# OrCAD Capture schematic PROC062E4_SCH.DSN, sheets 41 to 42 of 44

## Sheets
41 41. SoC POWER SUPPLY: size C; title: SoC POWER SUPPLY
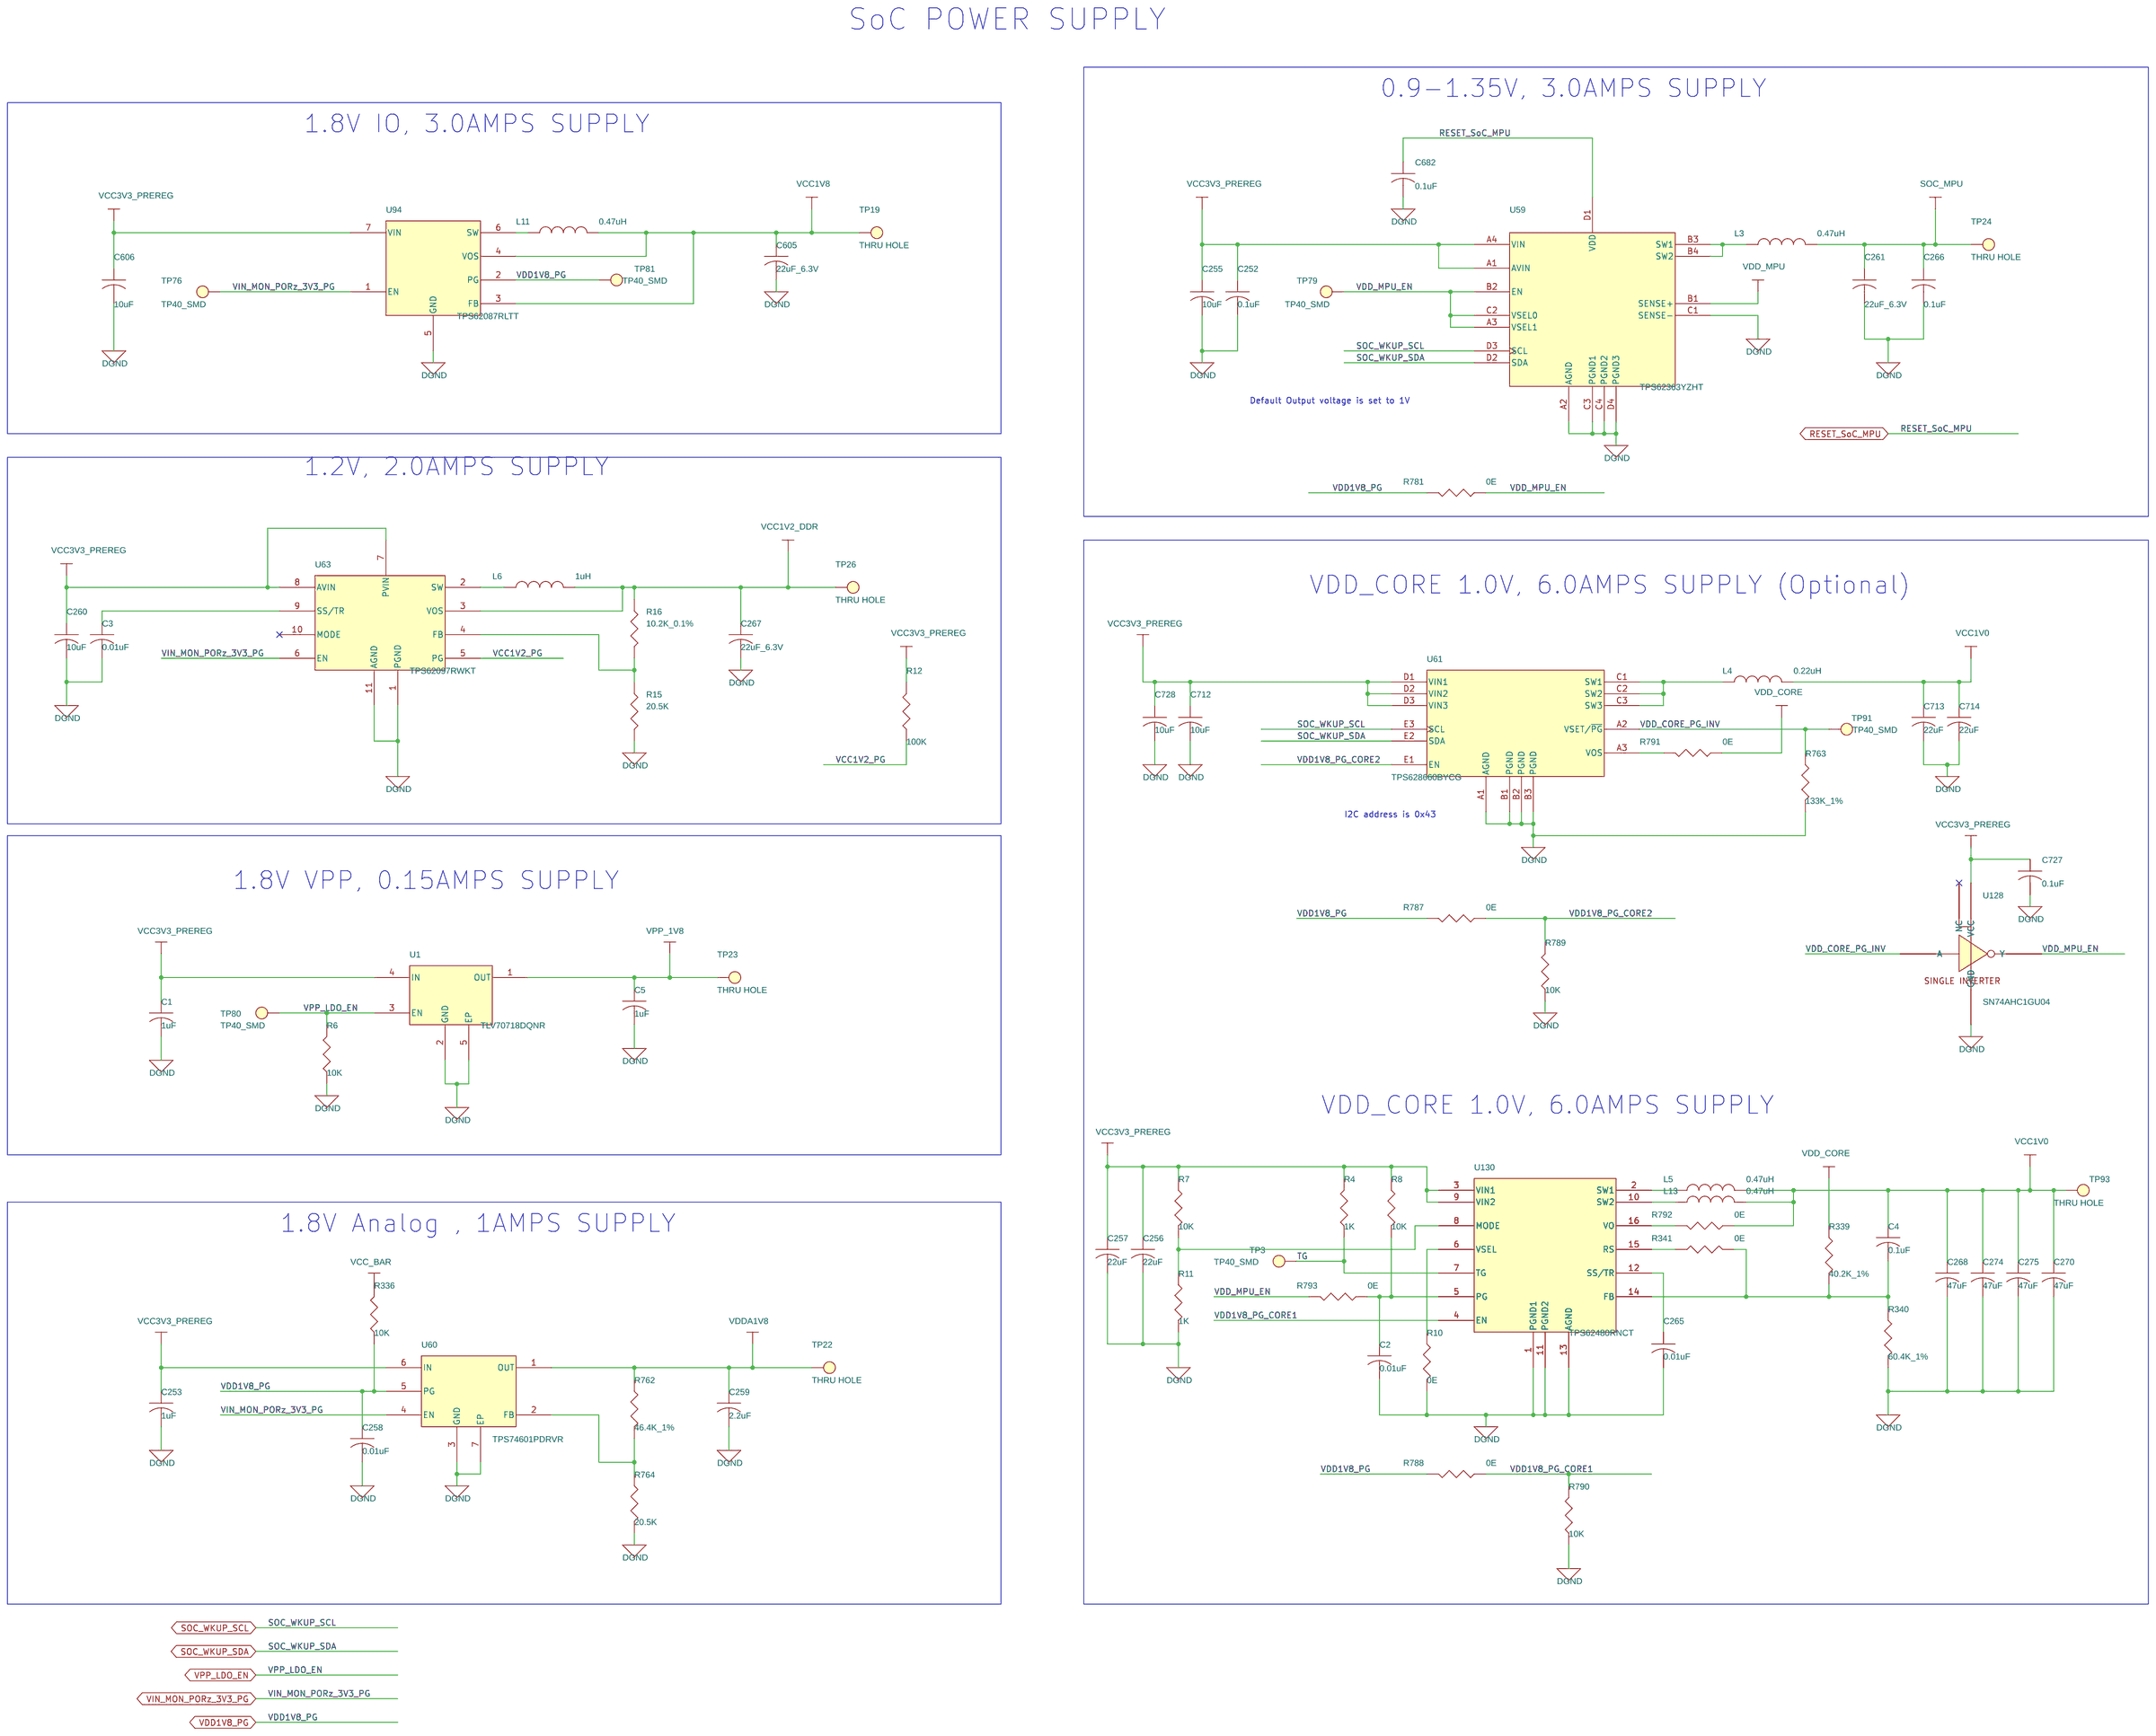
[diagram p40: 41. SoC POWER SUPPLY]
42 42. PERIPHERAL POWER SUPPLY: size C; title: PERIPHERAL POWER SUPPLY

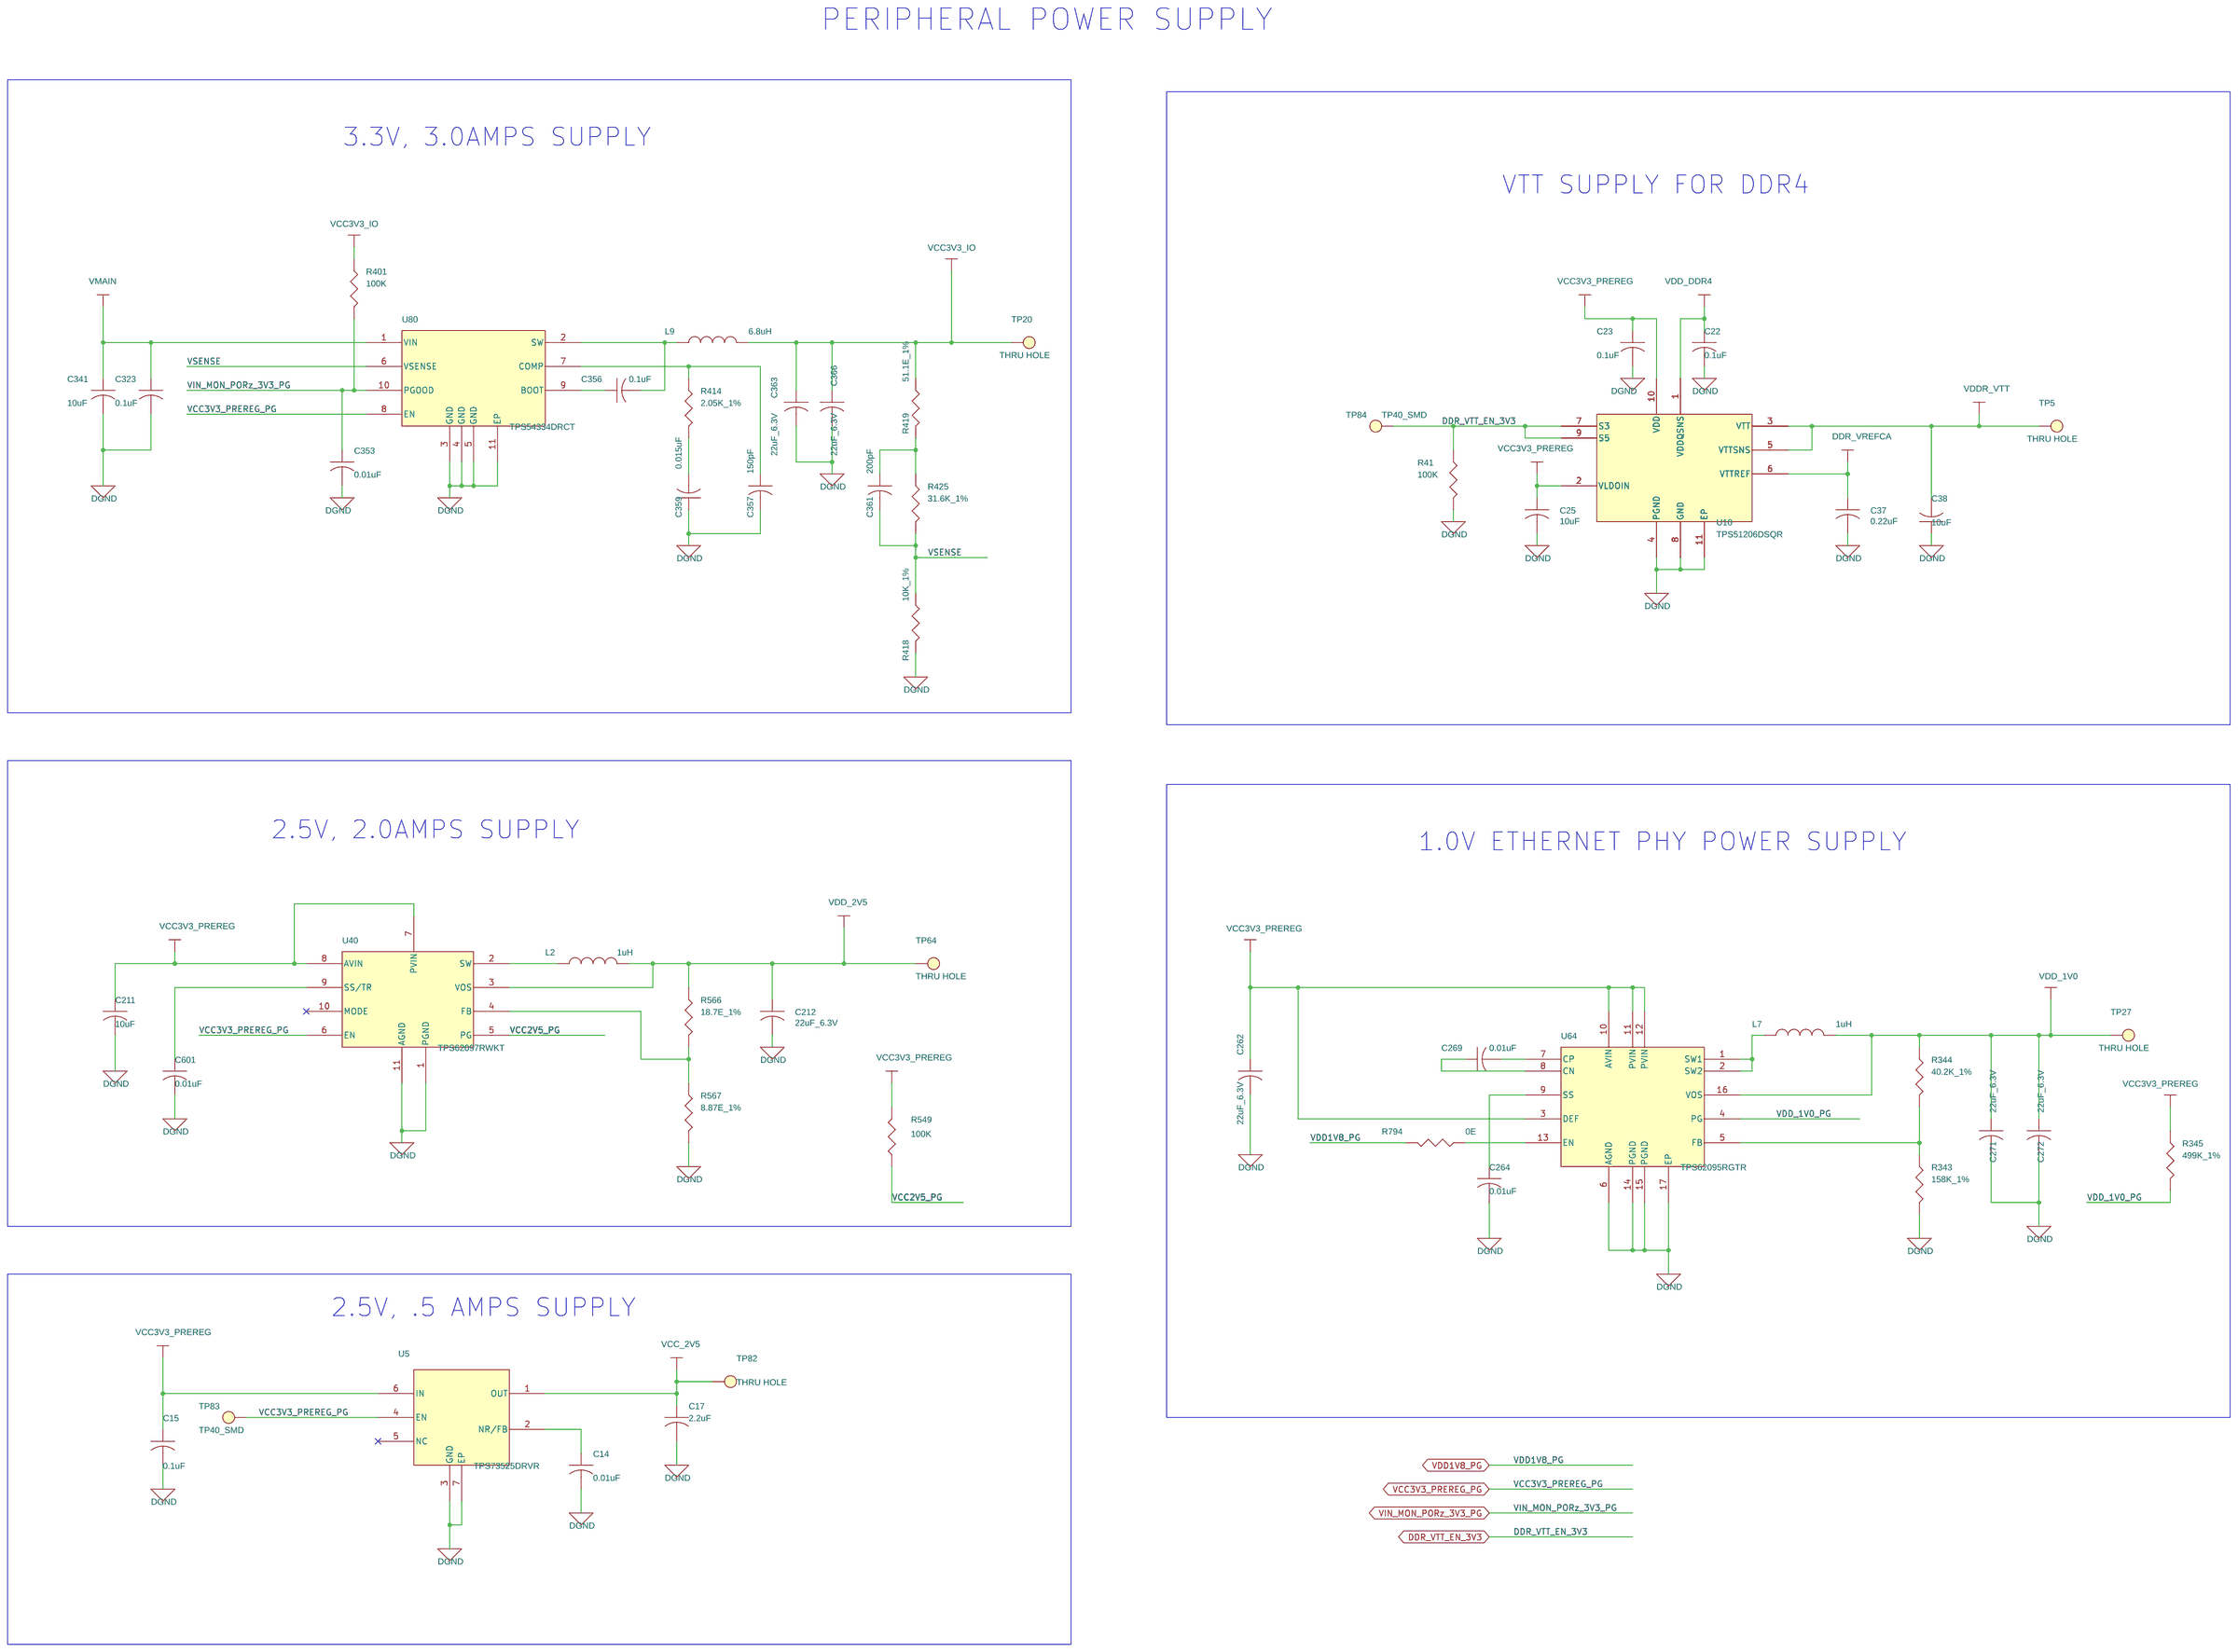
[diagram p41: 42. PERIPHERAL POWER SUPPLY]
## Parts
sheet 41. SoC POWER SUPPLY
C1  1uF  [CAP0603_1]
C2  0.01uF  [CAP0201_0-5]
C3  0.01uF  [CAP0201_0-5]
C4  0.1uF  [CAP0201_0-5]
C5  1uF  [CAP0603_1]
C252  0.1uF  [CAP0201_0-5]
C253  1uF  [CAP0603_1]
C255  10uF  [CAP1206_2]
C256  22uF  [CAP1206_2]
C257  22uF  [CAP1206_2]
C258  0.01uF  [CAP0201_0-5]
C259  2.2uF  [CAP0402_0-75]
C260  10uF  [CAP0603_1]
C261  22uF_6.3V  [CAP0603]
C265  0.01uF  [CAP0402_0-75]
C266  0.1uF  [CAP0201_0-5]
C267  22uF_6.3V  [CAP0603]
C268  47uF  [CAP0603_1]
C270  47uF  [CAP0603_1]
C274  47uF  [CAP0603_1]
C275  47uF  [CAP0603_1]
C605  22uF_6.3V  [CAP0603]
C606  10uF  [CAP1206_2]
C682  0.1uF  [CAP0201_0-5]
C712  10uF  [CAP0603_1]
C713  22uF  [CAP1206_2]
C714  22uF  [CAP1206_2]
C727  0.1uF  [CAP0201_0-5]
C728  10uF  [CAP0603_1]
L3  0.47uH  [IND_XEL4030_170X170_SMD_1-6]
L4  0.22uH  [IND_XAL4020_170X170_SMD_2-1]
L5  0.47uH  [IND_XEL4030_170X170_SMD_1-6]
L6  1uH  [IND_IHLP2020AB_210X210_SMD_1-2]
L11  0.47uH  [IND_XEL4030_170X170_SMD_1-6]
L13  0.47uH  [IND_XEL4030_170X170_SMD_1-6]
R4  1K  [RES0201]
R6  10K  [RES0402_0-5]
R7  10K  [RES0402_0-5]
R8  10K  [RES0402_0-5]
R10  0E  [RES0402_0-5]
R11  1K  [RES0201]
R12  100K  [RES0402_0-5]
R15  20.5K  [RES0402]
R16  10.2K_0.1%  [RES0402]
R336  10K  [RES0402_0-5]
R339  40.2K_1%  [RES0402_0-5]
R340  60.4K_1%  [RES0402_0-5]
R341  0E  [RES0402_0-5]
R762  46.4K_1%  [RES0402]
R763  133K_1%  [RES0402_0-5]
R764  20.5K  [RES0402]
R781  0E  [RES0402_0-5]
R787  0E  [RES0402_0-5]
R788  0E  [RES0402_0-5]
R789  10K  [RES0402_0-5]
R790  10K  [RES0402_0-5]
R791  0E  [RES0402_0-5]
R792  0E  [RES0402_0-5]
R793  0E  [RES0402_0-5]
TP3  TP40_SMD  [TP40_SMD]
TP19  THRU HOLE  [TP_40X65]
TP22  THRU HOLE  [TP_40X65]
TP23  THRU HOLE  [TP_40X65]
TP24  THRU HOLE  [TP_40X65]
TP26  THRU HOLE  [TP_40X65]
TP76  TP40_SMD  [TP40_SMD]
TP79  TP40_SMD  [TP40_SMD]
TP80  TP40_SMD  [TP40_SMD]
TP81  TP40_SMD  [TP40_SMD]
TP91  TP40_SMD  [TP40_SMD]
TP93  THRU HOLE  [TP_40X65]
U1  TLV70718DQNR  [X2SON4_TLV71318P_40X40_0-4]
U59  TPS62363YZHT  [DSBGA16_19-68_80X80_0-7]
U60  TPS74601PDRVR  [SON6_25-59_85X85_0-8]
U61  TPS628660BYCG  [WCSP15_13-77_40X70_0-5]
U63  TPS62097RWKT  [VQFNHR11_TPS62097_80X80_1]
U94  TPS62087RLTT  [VSONHR7_TPS62085_80X80_1]
U128  SN74AHC1GU04  [SOT23-5]
U130  TPS62480RNCT  [VQFNHR16_TPS62480_100X120_1]
sheet 42. PERIPHERAL POWER SUPPLY
C14  0.01uF  [CAP0201_0-5]
C15  0.1uF  [CAP0201_0-5]
C17  2.2uF  [CAP0402_0-75]
C22  0.1uF  [CAP0201_0-5]
C23  0.1uF  [CAP0201_0-5]
C25  10uF  [CAP0603_1]
C37  0.22uF  [CAP0402_0-75]
C38  10uF  [CAP0603_1]
C211  10uF  [CAP0603_1]
C212  22uF_6.3V  [CAP0603]
C262  22uF_6.3V  [CAP0603]
C264  0.01uF  [CAP0201_0-5]
C269  0.01uF  [CAP0201_0-5]
C271  22uF_6.3V  [CAP0603]
C272  22uF_6.3V  [CAP0603]
C323  0.1uF  [CAP0603_1]
C341  10uF  [CAP1206_2]
C353  0.01uF  [CAP0201_0-5]
C356  0.1uF  [CAP0201_0-5]
C357  150pF  [CAP0402_0-75]
C359  0.015uF  [CAP0402]
C361  200pF  [CAP0402_0-75]
C363  22uF_6.3V  [CAP0603]
C366  22uF_6.3V  [CAP0603]
C601  0.01uF  [CAP0201_0-5]
L2  1uH  [IND_IHLP2020AB_210X210_SMD_1-2]
L7  1uH  [IND_XFL4020_170X170_SMD_2-1]
L9  6.8uH  [IND_74439346068_260X270_SMD_6-1]
R41  100K  [RES0402_0-5]
R343  158K_1%  [RES0402_0-5]
R344  40.2K_1%  [RES0402_0-5]
R345  499K_1%  [RES0402]
R401  100K  [RES0402_0-5]
R414  2.05K_1%  [RES0402]
R418  10K_1%  [RES0402_0-5]
R419  51.1E_1%  [RES0402_0-5]
R425  31.6K_1%  [RES0402]
R549  100K  [RES0402_0-5]
R566  18.7E_1%  [RES0402]
R567  8.87E_1%  [RES0402]
R794  0E  [RES0402_0-5]
TP5  THRU HOLE  [TP_40X65]
TP20  THRU HOLE  [TP_40X65]
TP27  THRU HOLE  [TP_40X65]
TP64  THRU HOLE  [TP_40X65]
TP82  THRU HOLE  [TP_40X65]
TP83  TP40_SMD  [TP40_SMD]
TP84  TP40_SMD  [TP40_SMD]
U5  TPS73525DRVR  [SON6_25-59_85X85_0-8]
U10  TPS51206DSQR  [DFN10_15-74_80X80_0-8]
U40  TPS62097RWKT  [VQFNHR11_TPS62097_80X80_1]
U64  TPS62095RGTR  [QFN16_19-68_120X120_1]
U80  TPS54334DRCT  [SON10_19-68_125X125_1]

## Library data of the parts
C1 C5 C253 = CAP: CAP CERAMIC 1uF 25V 10% X5R 0603; Chkd/date: MANIRAJA/230118; Crtd /date: MANIRAJA/230118; Custom_Duty: 15%; Customs_HS_Code: 85322990; Distributor_name: DIGIKEY; Distributor_part_number: 478-5142-1-ND; Height: 0.94MM; Mfr_name: AVX CORPORATION; Mfr_part_number: 06033D105KAT2A; Mistral Part No: 120010080040-R; Package: 0603; Part_type: CAPACITORS\CERAMIC; Project: TI_MAXIE_CPB; RoHS: RoHS; Temperature: -55°C+85°C; Tolerance: 10%; Voltage: 25V; Wattage: NA; Weight: 2mg; Datasheet: Y:\MIS_DATABASE\DATASHEETS\CAPACITORS\AVX_MLC.PDF
C2 C3 C14 C258 C264 C269 C353 C601 = CAP: CAP CERAMIC 0.01uF 25V 10% X5R 0201; Chkd/date: MANIRAJA/230118; Crtd /date: MANIRAJA/230118; Custom_Duty: 15%; Customs_HS_Code: 85322990; Distributor_name: DIGIKEY; Distributor_part_number: GRM033R61E103KA12J-ND; Height: 0.33MM; Mfr_name: MURATA; Mfr_part_number: GRM033R61E103KA12J; Mistral Part No: 120018010007-R; Package: 0201; Part_type: CAPACITORS\CERAMIC; Project: TI_MAXIE_CPB; RoHS: RoHS; Temperature: -55°C+85°C; Tolerance: 10%; Voltage: 25V; Wattage: NA; Weight: 0.33mg; Datasheet: Y:\MIS_DATABASE\DATASHEETS\CAPACITORS\GRM033R61E103KA12.PDF
C4 C15 C22 C23 C252 C266 C356 C682 C727 = CAP: CAP CERAMIC 0.1uF 16V 10% X5R 0201; Chkd/date: MANIRAJA/120218; Crtd /date: MANIRAJA/120218; Custom_Duty: 15%; Customs_HS_Code: 85322990; Distributor_name: DIGIKEY; Distributor_part_number: 490-16742-1-ND; Height: 0.33MM; Mfr_name: MURATA; Mfr_part_number: GRM033R61C104KE84J; Mistral Part No: 120009030072-R; Package: 0201; Part_type: CAPACITORS\CERAMIC; Project: TI_MAXIE_CPB; RoHS: RoHS; Temperature: -55°C+85°C; Tolerance: 10%; Voltage: 16V; Wattage: NA; Weight: 0.33mg; Datasheet: Y:\MIS_DATABASE\DATASHEETS\CAPACITORS\GRM033R61C104KE84.PDF
C255 C341 = CAP: CAP CERAMIC 10uF 50V 10% X5R 1206; Chkd/date: VASANTHA/190814; Crtd /date: BAVISH/230611; Custom_Duty: 15%; Customs_HS_Code: 85322990; Distributor_name: DIGIKEY; Distributor_part_number: 445-5998-1-ND; Footprint Path: Y:\MIS_DATABASE\Library\ALTIUM_TOOL\PCB_FOOTPRINTS\Altium_Footprint_Lib.PcbLib; Height: 1.90MM; Library Path: Y:\MIS_DATABASE\Library\ALTIUM_TOOL\SCHEMATICS_PARTS\MS_DISCRETE_Library.schlib; Mfr_name: TDK CORPORATION; Mfr_part_number: C3216X5R1H106K160AB; Mistral Part No: 120016030005-R; Package: 1206; Part_type: CAPACITORS\CERAMIC; Project: ITS-SINGAL_COND_CARD; RoHS: RoHS; Temperature: -55°C+85°C; Tolerance: 10%; Voltage: 50V; Wattage: NA; Weight: 16.2mg; Datasheet: Y:\MIS_DATABASE\DATASHEETS\CAPACITORS\TDK_C-SER-JUL17.PDF
C256 C257 C713 C714 = CAP: CAP CERAMIC 22uF 16V 20% X7R 1206; Chkd/date: VASANTHA/170117; Crtd /date: VASANTHA/170117; Custom_Duty: 15%; Customs_HS_Code: 85322990; Distributor_name: DIGIKEY; Distributor_part_number: 587-4319-1-ND; Height: 1.90MM; Mfr_name: TAIYO YUDEN; Mfr_part_number: EMK316BB7226ML-T; Mistral Part No: 120017010003-R; Package: 1206; Part_type: CAPACITORS\CERAMIC; Project: TRMM_SMART-M_PS; RoHS: RoHS; Temperature: -55°C+125°C; Tolerance: 20%; Voltage: 16V; Wattage: NA; Weight: 16.2mg; Datasheet: Y:\MIS_DATABASE\DATASHEETS\CAPACITORS\EMK316BB7226ML.PDF
C17 C259 = CAP: CAP CERAMIC 2.2uF 10V 20% X5R 0402; Chkd/date: MANIRAJA/240118; Crtd /date: MANIRAJA/240118; Custom_Duty: 15%; Customs_HS_Code: 85322990; Distributor_name: DIGIKEY; Distributor_part_number: 490-12254-1-ND; Height: 0.55MM; Mfr_name: MURATA; Mfr_part_number: GRT155R61A225ME01D; Mistral Part No: 120018010016-R; Package: 0402; Part_type: CAPACITORS\CERAMIC; Project: TI_MAXIE_CPB; RoHS: RoHS; Temperature: -55°C+85°C; Tolerance: 20%; Voltage: 10V; Wattage: NA; Weight: 0.65mg; Datasheet: Y:\MIS_DATABASE\DATASHEETS\CAPACITORS\GRT155R61A225ME01.PDF
C25 C38 C211 C260 C712 C728 = CAP: CAP CERAMIC 10uF 10V 10% X5R 0603; Chkd/date: MANIRAJA/230118; Crtd /date: MANIRAJA/230118; Custom_Duty: 15%; Customs_HS_Code: 85322990; Distributor_name: DIGIKEY; Distributor_part_number: 478-10766-1-ND; Height: 0.94MM; Mfr_name: AVX CORPORATION; Mfr_part_number: 0603ZD106KAT2A; Mistral Part No: 120010080001-R; Package: 0603; Part_type: CAPACITORS\CERAMIC; Project: TI_MAXIE_CPB; RoHS: RoHS; Temperature: -55°C+85°C; Tolerance: 10%; Voltage: 10V; Wattage: NA; Weight: 2mg; Datasheet: Y:\MIS_DATABASE\DATASHEETS\CAPACITORS\AVX_MLC.PDF
C212 C261 C262 C267 C271 C272 C363 C366 C605 = CAP: CAP CERAMIC 22uF 6.3V 20% X5R 0603; Alternate_mfr_name_A: YAGEO AMERICA; Alternate_mfr_part_number_A: CC0603MRX5R5BB226; Chkd/date: JEBRAN/090915; Crtd /date: JEBRAN/090915; Custom_Duty: 15%; Customs_HS_Code: 85322990; Distributor_name: DIGIKEY; Distributor_name_A: DIGIKEY; Distributor_part_number: 490-7611-2-ND; Distributor_part_number_A: 311-1815-1-ND; Height: 1.00MM; Mfr_name: MURATA; Mfr_part_number: GRM188R60J226MEA0; Mistral Part No: 120015090007-R; Package: 0603; Part_type: CAPACITORS\CERAMIC; Project: OCTBTS_3000; RoHS: RoHS; Temperature: -55°C+85°C; Tolerance: 20%; Voltage: 6.3V; Wattage: NA; Weight: NA; Datasheet: Y:\MIS_DATABASE\DATASHEETS\CAPACITORS\GRM188SERIES.PDF
C265 = CAP: CAP CERAMIC 0.01uF 10V 10% X7R 0402; Chkd/date: VASANTHA/061216; Crtd /date: MAZHAR/201005; Custom_Duty: 15%; Customs_HS_Code: 85322990; Distributor_name: DIGIKEY; Distributor_part_number: 478-7890-1-ND; Height: 0.56MM; Mfr_name: AVX CORPORATION; Mfr_part_number: 0402ZC103KAT2A; Mistral Part No: 120009030017-R; Package: 0402; Part_type: CAPACITORS\CERAMIC; Project: ADR; RoHS: RoHS; Temperature: -55°C+125°C; Tolerance: 10%; Voltage: 10V; Wattage: NA; Weight: 0.65mg; Datasheet: Y:\MIS_DATABASE\DATASHEETS\CAPACITORS\AVX_MLC.PDF
C268 C270 C274 C275 = CAP: CAP CERAMIC 47uF 6.3V 20% X5R 0603; Chkd/date: VASANTHA/211116; Crtd /date: MANIRAJA/211116; Custom_Duty: 15%; Customs_HS_Code: 85322990; Distributor_name: DIGIKEY; Distributor_part_number: 490-13247-1-ND; Height: 0.90MM; Mfr_name: MURATA; Mfr_part_number: GRM188R60J476ME15D; Mistral Part No: 120016110001-R; Package: 0603; Part_type: CAPACITORS\CERAMIC; Project: DLRL_3U_ESM_VPX; RoHS: RoHS; Temperature: -55°C+85°C; Tolerance: 20%; Voltage: 6.3V; Wattage: NA; Weight: 9.10mg; Datasheet: Y:\MIS_DATABASE\DATASHEETS\CAPACITORS\GRM188SERIES.PDF
C606 = CAP: CAP CERAMIC 10uF 16V 10% X7R 1206; Chkd/date: VASANTHA/291216; Crtd /date: MAZHAR/120909; Custom_Duty: 15%; Customs_HS_Code: 85322990; Distributor_name: DIGIKEY; Distributor_part_number: 399-3525-1-ND; Height: 1.80MM; Mfr_name: KEMET; Mfr_part_number: C1206C106K4RACTU; Mistral Part No: 120009090010-R; Package: 1206; Part_type: CAPACITORS\CERAMIC; Project: ADE POWER SUPPLY; RoHS: RoHS; Temperature: -55°C+125°C; Tolerance: 10%; Voltage: 16V; Wattage: NA; Weight: 16.2mg; Datasheet: Y:\MIS_DATABASE\DATASHEETS\CAPACITORS\KEMET-C08_X.PDF
L3 L5 L11 L13 = INDUCTOR: IND POWER 0.47uH 20% 11.2A SMD; Chkd/date: MANIRAJA/150218; Crtd /date: ALVY/150218; Custom_Duty: 24%; Customs_HS_Code: 85437099; Distributor_name: MOUSER; Distributor_part_number: 994-XFL4015-471MEB; Footprint Path: Y:\MIS_DATABASE\Library\ALTIUM_TOOL\PCB_FOOTPRINTS\Altium_Footprint_Lib.PcbLib; Height: 1.60MM; Library Path: Y:\MIS_DATABASE\Library\ALTIUM_TOOL\SCHEMATICS_PARTS\MS_DISCRETE_Library.schlib; Mfr_name: COILCARFT; Mfr_part_number: XFL4015-471MEB; Mistral Part No: 130018020040-R; Package: SMD; Project: TI_MAXIE_CPB; RoHS: RoHS; Temperature: -40°C+125°C; Tolerance: 20%; Voltage: NA; Wattage: NA; Weight: 95mg; Datasheet: Y:\MIS_DATABASE\DATASHEETS\DISCRETES\INDUCTORS\XFL4015.PDF
L4 = INDUCTOR: IND POWER 0.22uH 16.8A 20% SMD; Chkd/date: MANIRAJA/100619; Crtd /date: MANIRAJA/100619; Custom_Duty: 24%; Customs_HS_Code: 85437099; Distributor_name: MOUSER; Distributor_part_number: 994-XAL4020-221MEB; Footprint Path: Y:\MIS_DATABASE\Library\ALTIUM_TOOL\PCB_FOOTPRINTS\Altium_Footprint_Lib.PcbLib; Height: 2.10MM; Library Path: Y:\MIS_DATABASE\Library\ALTIUM_TOOL\SCHEMATICS_PARTS\MS_DISCRETE_Library.schlib; Mfr_name: COILCARFT; Mfr_part_number: XAL4020-221MEB; Mistral Part No: 130019060012-R; Package: SMD; Project: TI_MAXIE_CPB; RoHS: RoHS; Temperature: -40°C+125°C; Tolerance: 20%; Voltage: NA; Wattage: NA; Weight: 180mg; Datasheet: Y:\MIS_DATABASE\DATASHEETS\DISCRETES\INDUCTORS\XAL40XX.PDF
L2 L6 = INDUCTOR: IND POWER 1uH 4.4A 20% SMD; Chkd/date: VASANTHA/170317; Crtd /date: MANIRAJA/160317; Custom_Duty: 24%; Customs_HS_Code: 85437099; Distributor_name: DIGIKEY; Distributor_part_number: 541-1704-1-ND; Height: 1.20MM; Mfr_name: VISHAY; Mfr_part_number: IHLP2020ABER1R0M01; Mistral Part No: 130017030015-R; Package: SMD; Project: ADA_3U_FMC; RoHS: RoHS; Temperature: -55°C+125°C; Tolerance: 20%; Voltage: NA; Wattage: NA; Weight: 200mg; Datasheet: Y:\MIS_DATABASE\DATASHEETS\DISCRETES\INDUCTORS\IHLP2020AB.PDF
R4 R11 = RESISTOR: RES 1K 1/20W 5% 0201; Chkd/date: JEBRAN/110815; Crtd /date: JEBRAN/110815; Custom_Duty: 15%; Customs_HS_Code: 85332119; Distributor_name: DIGIKEY; Distributor_part_number: 541-1.00KAABCT-ND; Height: 0.28MM; Mfr_name: VISHAY; Mfr_part_number: CRCW02011K00FKED; Mistral Part No: 110015080014-R; Package: 0201; Part_type: RESISTORS\FIXED; Project: OCTASIC_3000; RoHS: RoHS; Temperature: -55°C+155°C; Tolerance: 5%; Voltage: NA; Wattage: 1/20W; Weight: NA; Datasheet: Y:\MIS_DATABASE\DATASHEETS\RESISTORS\CRCW0201.PDF
R6-R8 R336 R789 R790 = RESISTOR: RES 10K 1/16W 5% 0402; Chkd/date: VASANTHA/061216; Crtd /date: MAZHAR/230805; Custom_Duty: 15%; Customs_HS_Code: 85332119; Distributor_name: DIGIKEY; Distributor_part_number: 311-10KJRCT-ND; Footprint Path: Y:\MIS_DATABASE\Library\ALTIUM_TOOL\PCB_FOOTPRINTS\Altium_Footprint_Lib.PcbLib; Height: 0.40MM; Library Path: Y:\MIS_DATABASE\Library\ALTIUM_TOOL\SCHEMATICS_PARTS\MS_DISCRETE_Library.schlib; Mfr_name: YAGEO AMERICA; Mfr_part_number: RC0402JR-0710KL; Mistral Part No: 110009030208-R; Package: 0402; Part_type: RESISTORS\FIXED; Project: HSE; RoHS: Pb-Free; Temperature: -55°C+155°C; Tolerance: 5%; Voltage: NA; Wattage: 1/16W; Weight: 0.65mg; Datasheet: Y:\MIS_DATABASE\DATASHEETS\RESISTORS\YAGEO-RC0402.PDF
R10 R341 R781 R787 R788 R791-R794 = RESISTOR: RES 0E 1/16W 0402; Chkd/date: VASANTHA/201216; Crtd /date: MUDDU/190810; Custom_Duty: 15%; Customs_HS_Code: 85332119; Distributor_name: DIGIKEY; Distributor_part_number: 541-0.0JCT-ND; Footprint Path: Y:\MIS_DATABASE\Library\ALTIUM_TOOL\PCB_FOOTPRINTS\Altium_Footprint_Lib.PcbLib; Height: 0.40MM; Library Path: Y:\MIS_DATABASE\Library\ALTIUM_TOOL\SCHEMATICS_PARTS\MS_DISCRETE_Library.schlib; Mfr_name: VISHAY; Mfr_part_number: CRCW04020000Z0ED; Mistral Part No: 110010080019-P; Package: 0402; Part_type: RESISTORS\FIXED; Project: PB_BUGBASE; RoHS: Pb-Free; Temperature: -55°C+155°C; Tolerance: NA; Voltage: NA; Wattage: 1/16W; Weight: 0.65g/1000pcs; Datasheet: Y:\MIS_DATABASE\DATASHEETS\RESISTORS\CRCW0603.PDF
R12 R41 R401 R549 = RESISTOR: RES 100K 1/16W 5% 0402; Chkd/date: VASANTHA/061216; Crtd /date: BAVISH/010611; Custom_Duty: 15%; Customs_HS_Code: 85332119; Distributor_name: DIGIKEY; Distributor_part_number: 541-100KJCT-ND; Height: 0.40MM; Mfr_name: VISHAY; Mfr_part_number: CRCW0402100KJNED; Mistral Part No: 110011060002-R; Package: 0402; Part_type: RESISTORS\FIXED; Project: AM4515_EVM_LCD; RoHS: RoHS; Temperature: -55°C+155°C; Tolerance: 5%; Voltage: NA; Wattage: 1/16W; Weight: 0.65mg; Datasheet: Y:\MIS_DATABASE\DATASHEETS\RESISTORS\CRCW0603.PDF
R15 R764 = RESISTOR: RES 20.5K 1/10W 1% 0402; Chkd/date: MAZHAR/0141010; Crtd /date: BAVISH/290910; Custom_Duty: 15%; Customs_HS_Code: 85332119; Distributor_name: DIGIKEY; Distributor_part_number: P20.5KLCT-ND; Footprint Path: Y:\MIS_DATABASE\Library\ALTIUM_TOOL\PCB_FOOTPRINTS\Altium_Footprint_Lib.PcbLib; Height: 0.40MM; Library Path: Y:\MIS_DATABASE\Library\ALTIUM_TOOL\SCHEMATICS_PARTS\MS_DISCRETE_Library.schlib; Mfr_name: PANASONIC-ECG; Mfr_part_number: ERJ-2RKF2052X; Mistral Part No: 110010090063-R; Package: 0402; Part_type: RESISTORS\FIXED; Project: ITS; RoHS: RoHS; Temperature: -55°C+125°C; Tolerance: 1%; Wattage: 1/10W; Weight: 0.8/1000g; Datasheet: Y:\MIS_DATABASE\DATASHEETS\RESISTORS\ERJ2R.PDF
R16 = RESISTOR: RES 10.2K 1/16W 0.1% 0402; Chkd/date: MAZHAR/200611; Crtd /date: BAVISH/240511; Custom_Duty: 15%; Customs_HS_Code: 85332119; Distributor_name: DIGIKEY; Distributor_part_number: TNP10.2KDACT-ND; Height: 0.40MM; Mfr_name: VISHAY; Mfr_part_number: TNPW040210K2BEED; Mistral Part No: 110011050017-R; Package: 0402; Part_type: RESISTORS\FIXED; Project: HMC; RoHS: RoHS; Temperature: -55°C+125°C; Tolerance: 0.1%; Voltage: NA; Wattage: 1/16W; Weight: 0.65/1000g; Datasheet: Y:\MIS_DATABASE\DATASHEETS\RESISTORS\VISHAY_TNPW.PDF
R339 R344 = RESISTOR: RES 40.2K 1/16W 1% 0402; Chkd/date: VASANTHA/291216; Crtd /date: MAZHAR/170505; Custom_Duty: 15%; Customs_HS_Code: 85332119; Distributor_name: DIGIKEY; Distributor_part_number: 311-40.2KLRDKR-ND; Footprint Path: Y:\MIS_DATABASE\Library\ALTIUM_TOOL\PCB_FOOTPRINTS\Altium_Footprint_Lib.PcbLib; Height: 0.40MM; Library Path: Y:\MIS_DATABASE\Library\ALTIUM_TOOL\SCHEMATICS_PARTS\MS_DISCRETE_Library.schlib; Mfr_name: YAGEO AMERICA; Mfr_part_number: RC0402FR-0740K2L; Mistral Part No: 110009030811; Package: 0402; Part_type: RESISTORS\FIXED; Project: G4SLIM; RoHS: RoHS; Temperature: -55°C+155°C; Tolerance: 1%; Voltage: NA; Wattage: 1/16W; Weight: 0.65mg; Datasheet: Y:\MIS_DATABASE\DATASHEETS\RESISTORS\YAGEO_RES.PDF
R340 = RESISTOR: RES 60.4K 1/16W 1% 0402; Chkd/date: VASANTHA/281216; Crtd /date: USMAN/201112; Cust_part_number: 4700-80042E; Custom_Duty: 15%; Customs_HS_Code: 85332119; Distributor_name: DIGIKEY; Distributor_part_number: 311-60.4KLRCT-ND; Height: 0.40MM; Mfr_name: YAGEO AMERICA; Mfr_part_number: RC0402FR-0760K4L; Mistral Part No: 110012110012-R; Package: 0402; Part_type: RESISTORS\FIXED; Project: ITS-CONTROLER_CARD; RoHS: RoHS; Temperature: -55°C+155°C; Tolerance: 1%; Voltage: NA; Wattage: 1/16W; Weight: 0.65mg; Datasheet: Y:\MIS_DATABASE\DATASHEETS\RESISTORS\YAGEO-RC0402.PDF
R762 = RESISTOR: RES 46.4K 1/16W 1% 0402; Chkd/date: USMAN/230413; Crtd /date: USMAN/180213; Custom_Duty: 15%; Customs_HS_Code: 85332119; Distributor_name: DIGIKEY; Distributor_part_number: 541-46.4KLCT-ND; Footprint Path: Y:\MIS_DATABASE\Library\ALTIUM_TOOL\PCB_FOOTPRINTS\Altium_Footprint_Lib.PcbLib; Height: 0.40MM; Library Path: Y:\MIS_DATABASE\Library\ALTIUM_TOOL\SCHEMATICS_PARTS\MS_DISCRETE_Library.schlib; Mfr_name: VISHAY; Mfr_part_number: CRCW040246K4FKED; Mistral Part No: 110013020001-R; Package: 0402; Part_type: RESISTORS\FIXED; Project: ITS-SCP; RoHS: RoHS; Temperature: -55°C+155°C; Tolerance: 1%; Voltage: NA; Wattage: 1/16W; Weight: 0.65mg; Datasheet: Y:\MIS_DATABASE\DATASHEETS\RESISTORS\CRCW0603.PDF
R763 = RESISTOR: RES 133K 1/10W 1% 0402; Chkd/date: MANIRAJA/161118; Crtd /date: ALVY/161118; Custom_Duty: 15%; Customs_HS_Code: 85332119; Distributor_name: DIGIKEY; Distributor_part_number: P133KLCT-ND; Footprint Path: Y:\MIS_DATABASE\Library\ALTIUM_TOOL\PCB_FOOTPRINTS\Altium_Footprint_Lib.PcbLib; Height: 0.40MM; Library Path: Y:\MIS_DATABASE\Library\ALTIUM_TOOL\SCHEMATICS_PARTS\MS_DISCRETE_Library.schlib; Mfr_name: PANASONIC-ECG; Mfr_part_number: ERJ-2RKF1333X; Mistral Part No: 110018110004-R; Package: 0402; Part_type: RESISTORS\FIXED; Project: TI_J7SVB_MAXWELL_VPS; RoHS: RoHS; Temperature: -55°C+155°C; Tolerance: 1%; Voltage: NA; Wattage: 1/10W; Weight: 0.8mg; Datasheet: Y:\MIS_DATABASE\DATASHEETS\RESISTORS\PAN-ERJSER_NOV17.PDF
TP3 TP76 TP79-TP81 TP83 TP84 TP91 = TESTPOINT: TESTPOINT CIR 40 SMD; Chkd/date: MAZHAR/190505; Crtd /date: MAZHAR/190505; Distributor_name: NA; Distributor_part_number: NA; Footprint Path: Y:\MIS_DATABASE\Library\ALTIUM_TOOL\PCB_FOOTPRINTS\Altium_Footprint_Lib.PcbLib; Height: NA; Library Path: Y:\MIS_DATABASE\Library\ALTIUM_TOOL\SCHEMATICS_PARTS\MS_DISCRETE_Library.schlib; MECHANICAL 3D STEP FILE: NA; Mfr_name: LOCAL; Mistral Part No: 130009030933; Package: SMD; Project: RAINIER-3; RoHS: NA; Temperature: NA; Tolerance: NA; Voltage: NA; Wattage: NA; Weight: NA; Datasheet: NA
TP5 TP19 TP20 TP22-TP24 TP26 TP27 TP64 TP82 TP93 = TESTPOINT: TESTPOINT 1.0MM DRILL PTH; Chkd/date: MAZHAR/271211; Crtd /date: SHREESHAIL/041005; Distributor_name: NA; Distributor_part_number: NA; Height: NA; Mfr_name: LOCAL; Mistral Part No: 130009030938; Package: THRU-HOLE; Part_type: MISC\TESTPOINT; Project: HSE; Datasheet: NA
U1 = TLV71318PDQNR_X2SON4: IC 200mA LOW IQ LOW NOISE LDO REGULATOR X2SON-4; Chkd/date: MANIRAJA/270218; Crtd /date: ALVY/260218; Custom_Duty: 15%; Customs_HS_Code: 85423100; Distributor_name: DIGIKEY; Distributor_part_number: 296-36768-1-ND; Footprint Path: Y:\MIS_DATABASE\Library\ALTIUM_TOOL\PCB_FOOTPRINTS\Altium_Footprint_Lib.PcbLib; Height: 0.40MM; Library Path: Y:\MIS_DATABASE\Library\ALTIUM_TOOL\SCHEMATICS_PARTS\MS_MISCPOWER_Library.schlib; Mfr_name: TEXAS INSTRUMENTS; Mistral Part No: 142018020038-R; Package: X2SON-4; Part_type: ICS\POWER\VOLTAGE REGULATOR; Project: TI_MAXIE_CPB; RoHS: RoHS; Temperature: -40°C+125°C; Tolerance: NA; Voltage: NA; Wattage: NA; Weight: 1.5mg; Datasheet: Y:\MIS_DATABASE\DATASHEETS\ICS\POWER\TLV707X.PDF
U59 = TPS6236X_DSBGA16: IC 3A PROCESSOR SUPPLY WITH I2C INTERFACE DSBGA16; Chkd/date: MANIRAJA/261017; Crtd /date: MANIRAJA/261017; Custom_Duty: 15%; Customs_HS_Code: 85423100; Distributor_name: DIGIKEY; Distributor_part_number: 296-30361-1-ND; Height: 0.63MM; Mfr_name: TEXAS INSTRUMENTS; Mistral Part No: 142017100016-R; Package: DSBGA16; Part_type: ICS\POWER\DC-DC CONVERTER; Project: TI_MAXIE_CPB; RoHS: RoHS; Temperature: -40°C+85°C; Tolerance: NA; Voltage: NA; Wattage: NA; Weight: NA; Datasheet: Y:\MIS_DATABASE\DATASHEETS\ICS\POWER\TPS6236XX.PDF
U60 = TPS74501_WSON6: IC 1A ADJ OUTPUT LDO WITH POWER-GOOD WSON6; Chkd/date: MANIRAJA/060619; Crtd /date: ALVY/060619; Custom_Duty: 15%; Customs_HS_Code: 85423100; Distributor_name: MOUSER; Distributor_part_number: 595-TPS74601PDRVR; Footprint Path: Y:\MIS_DATABASE\Library\ALTIUM_TOOL\PCB_FOOTPRINTS\Altium_Footprint_Lib.PcbLib; Height: 0.80MM; Library Path: Y:\MIS_DATABASE\Library\ALTIUM_TOOL\SCHEMATICS_PARTS\MS_MISCPOWER_Library.schlib; Mfr_name: TEXAS INSTRUMENTS; Mistral Part No: 142019060004-R; Package: WSON6; Part_type: ICS\POWER\VOLTAGE REGULATOR; Project: TI_MAXIE_CPB; RoHS: RoHS; Temperature: -40°C+125°C; Tolerance: NA; Voltage: NA; Wattage: NA; Weight: NA; Datasheet: Y:\MIS_DATABASE\DATASHEETS\ICS\POWER\TPS74601.PDF
U61 = TPS628660B_WCSP15: IC 2.4-5.5V I/P 6A O/P SYNC STEP DOWN CONVERTER WITH I2C INTERFACE WCSP15; Chkd/date: MANIRAJA/040619; Crtd /date: MANIRAJA/040619; Custom_Duty: 15%; Customs_HS_Code: 85423100; Distributor_name: NA; Distributor_part_number: NA; Footprint Path: Y:\MIS_DATABASE\Library\ALTIUM_TOOL\PCB_FOOTPRINTS\Altium_Footprint_Lib.PcbLib; Height: 0.50MM; Library Path: Y:\MIS_DATABASE\Library\ALTIUM_TOOL\SCHEMATICS_PARTS\MS_MISCPOWER_Library.schlib; Mfr_name: TEXAS INSTRUMENTS; Mistral Part No: 142019060001; Package: WCSP15; Part_type: ICS\POWER\CONVERTER; Project: TI_MAXIE_CPB; RoHS: NA; Temperature: NA; Tolerance: NA; Voltage: NA; Wattage: NA; Weight: NA; Datasheet: Y:\MIS_DATABASE\DATASHEETS\ICS\POWER\TPS62866.PDF
U40 U63 = TPS62097RWKT_VQFNHR11: IC 2A SYNCHRONOUS STEP DOWN CONVERTER WITH IDCS CONTROL VQFN-HR11; Chkd/date: MANIRAJA/270917; Crtd /date: MANIRAJA/270917; Custom_Duty: 15%; Customs_HS_Code: 85423100; Distributor_name: DIGIKEY; Distributor_part_number: 296-43330-1-ND; Height: 1.00MM; Mfr_name: TEXAS INSTRUMENTS; Mistral Part No: 142017090025-R; Package: VQFN-HR11; Part_type: ICS\POWER\CONVERTER; Project: TI_MAXIE_CPB; RoHS: RoHS; Temperature: -40°C+125°C; Tolerance: NA; Voltage: NA; Wattage: NA; Weight: NA; Datasheet: Y:\MIS_DATABASE\DATASHEETS\ICS\POWER\TPS62097.PDF
U94 = TPS62085RLTR_VSONHR7: IC 3A 1.8V STEP DOWN CONVERTER WITH SHORT CIRCUIT PROTECTION VSON-HR7; Chkd/date: MANIRAJA/310818; Crtd /date: MANIRAJA/310818; Custom_Duty: 15%; Customs_HS_Code: 85423100; Distributor_name: DIGIKEY; Distributor_part_number: 296-37087-1-ND; Footprint Path: Y:\MIS_DATABASE\Library\ALTIUM_TOOL\PCB_FOOTPRINTS\Altium_Footprint_Lib.PcbLib; Height: 1.00MM; Library Path: Y:\MIS_DATABASE\Library\ALTIUM_TOOL\SCHEMATICS_PARTS\MS_MISCPOWER_Library.schlib; Mfr_name: TEXAS INSTRUMENTS; Mistral Part No: 142018080020-R; Package: VSON-HR7; Part_type: ICS\POWER\CONVERTER; Project: TI_MAXIE_CPB; RoHS: RoHS; Temperature: -40°C+125°C; Tolerance: NA; Voltage: NA; Wattage: NA; Weight: 8.8mg; Datasheet: Y:\MIS_DATABASE\DATASHEETS\ICS\POWER\TPS62085.PDF
U128 = SN74AHC1GU04DBVR_SOT23-5: IC SINGLE INVERTER GATE SOT23-5; Chkd/date: SHREESHAIL/120106; Crtd /date: MAZHAR/160805; Custom_Duty: 15%; Customs_HS_Code: 85423100; Distributor_name: DIGIKEY; Distributor_part_number: 296-1095-1-ND; Height: 1.45MM; Mfr_name: TEXAS INSTRUMENTS; Mfr_part_number: SN74AHC1GU04DBVR; Mistral Part No: 141009030206; Part_type: ICS\DIGITAL\GATES; Project: HSE; Datasheet: Y:\MIS_DATABASE\DATASHEETS\ICS\DIGITAL\GATES\SN74AHC1GU04.PDF
U130 = TPS62480RNCT_VQFNHR16: IC 2-PHASE STEP DOWN DC-DC CONVERTER VQFN-HR16; Chkd/date: MANIRAJA/220917; Crtd /date: MANIRAJA/220917; Custom_Duty: 15%; Customs_HS_Code: 85423100; Distributor_name: DIGIKEY; Distributor_part_number: 296-43867-1-ND; Height: 1.00MM; Mfr_name: TEXAS INSTRUMENTS; Mistral Part No: 142017090012-R; Package: VQFN-HR16; Part_type: ICS\POWER\DC-DC CONVERTER; Project: TI_MAXIE_CPB; RoHS: RoHS; Temperature: -40°C+125°C; Tolerance: NA; Voltage: NA; Wattage: NA; Weight: 46mg; Datasheet: Y:\MIS_DATABASE\DATASHEETS\ICS\POWER\TPS62480R.PDF
C37 = CAP: CAP CERAMIC 0.22uF 10V 10% X5R 0402; Chkd/date: VASANTHA/291216; Crtd /date: MAZHAR/170907; Custom_Duty: 15%; Customs_HS_Code: 85322990; Distributor_name: DIGIKEY; Distributor_part_number: 490-3910-1-ND; Height: 0.55MM; Mfr_name: MURATA; Mfr_part_number: GRM155R61A224KE19D; Mistral Part No: 120009030090-R; Package: 0402; Part_type: CAPACITORS\CERAMIC; Project: SMART VIEW_NVR; RoHS: RoHS; Temperature: -55°C+85°C; Tolerance: 10%; Voltage: 10V; Wattage: NA; Weight: 6mg; Datasheet: Y:\MIS_DATABASE\DATASHEETS\CAPACITORS\GRM188SERIES.PDF
C323 = CAP: CAP CERAMIC 0.1uF 50V 20% X7R 0603; Chkd/date: MANIRAJA/240118; Crtd /date: MANIRAJA/240118; Custom_Duty: 15%; Customs_HS_Code: 85322990; Distributor_name: DIGIKEY; Distributor_part_number: 399-7845-1-ND; Height: 0.95MM; Mfr_name: KEMET; Mfr_part_number: C0603C104M5RACTU; Mistral Part No: 120018010021-R; Package: 0603; Part_type: CAPACITORS\CERAMIC; Project: TI_MAXIE_CPB; RoHS: RoHS; Temperature: -55°C+125°C; Tolerance: 20%; Voltage: 50V; Wattage: NA; Weight: 2mg; Datasheet: Y:\MIS_DATABASE\DATASHEETS\CAPACITORS\KEMET-X7R-SER.PDF
C357 = CAP: CAP CERAMIC 150pF 50V 10% X7R 0402; Chkd/date: MANIRAJA/240118; Crtd /date: MANIRAJA/240118; Custom_Duty: 15%; Customs_HS_Code: 85322990; Distributor_name: DIGIKEY; Distributor_part_number: 732-7551-1-ND; Height: 0.55MM; Mfr_name: WURTH ELECTRONICS; Mfr_part_number: 885012205056; Mistral Part No: 120018010022-R; Package: 0402; Part_type: CAPACITORS\CERAMIC; Project: TI_MAXIE_CPB; RoHS: RoHS; Temperature: -55°C+125°C; Tolerance: 10%; Voltage: 50V; Wattage: NA; Weight: 0.65mg; Datasheet: Y:\MIS_DATABASE\DATASHEETS\CAPACITORS\'885012205056.PDF
C359 = CAP: CAP CERAMIC 0.015uF 16V 10% X7R 0402; Alternate_mfr_name_A: MURATA; Alternate_mfr_part_number_A: GRM155R71C153KA01D; Chkd/date: VASANTHA/211215; Crtd /date: VASANTHA/211215; Custom_Duty: 15%; Customs_HS_Code: 85322990; Distributor_name: DIGIKEY; Distributor_name_A: DIGIKEY; Distributor_part_number: 490-6329-1-ND; Distributor_part_number_A: 490-1314-1-ND; Height: 0.55MM; Mfr_name: MURATA; Mfr_part_number: GRM155R71C153KA01J; Mistral Part No: 120015120015-R; Package: 0402; Part_type: CAPACITORS\CERAMIC; Project: DLRL_NBSDR; RoHS: RoHS; Temperature: -55°C+125°C; Tolerance: 10%; Voltage: 16V; Wattage: NA; Weight: NA; Datasheet: Y:\MIS_DATABASE\DATASHEETS\CAPACITORS\GRM188SERIES.PDF
C361 = CAP: CAP CERAMIC 200pF 50V 5% C0G 0402; Chkd/date: MANIRAJA/130617; Crtd /date: MAZHAR/090909; Custom_Duty: 15%; Customs_HS_Code: 85322990; Distributor_name: DIGIKEY; Distributor_part_number: 490-3232-1-ND; Height: 0.55MM; Mfr_name: MURATA; Mfr_part_number: GRM1555C1H201JA01D; Mistral Part No: 120009090005-R; Package: 0402; Part_type: CAPACITORS\CERAMIC; Project: GOLDEN-I; RoHS: RoHS; Temperature: -55°C+125°C; Tolerance: 5%; Voltage: 50V; Wattage: NA; Weight: 6mg; Datasheet: Y:\MIS_DATABASE\DATASHEETS\CAPACITORS\MURATA_CMCC.PDF
L7 = INDUCTOR: IND POWER 1uH 8A 20% SMD; Chkd/date: VASANTHA/050117; Crtd /date: CHAITHANYA/290312; Custom_Duty: 24%; Customs_HS_Code: 85437099; Distributor_name: MOUSER; Distributor_part_number: 994-XFL4020-102MEC; Height: 2.10MM; Mfr_name: COIL CRAFT; Mfr_part_number: XFL4020-102MEC; Mistral Part No: 130012030053-R; Package: SMD; Project: IRIS; RoHS: RoHS; Temperature: -40°C+85°C; Tolerance: 20%; Voltage: NA; Wattage: NA; Weight: 169mg; Datasheet: Y:\MIS_DATABASE\DATASHEETS\DISCRETES\INDUCTORS\XFL4020.PDF
L9 = INDUCTOR: IND POWER 6.8uH 6.5A 20% SMD; Chkd/date: MANIRAJA/171017; Crtd /date: MANIRAJA/171017; Custom_Duty: 24%; Customs_HS_Code: 85437099; Distributor_name: DIGIKEY; Distributor_part_number: 732-10705-1-ND; Height: 6.10MM; Mfr_name: WURTH ELECTRONICS; Mfr_part_number: 74439346068; Mistral Part No: 130017100019-R; Package: SMD; Project: TI_MAXIE_CPB; RoHS: RoHS; Temperature: -40°C+125°C; Tolerance: 20%; Voltage: NA; Wattage: NA; Weight: NA; Datasheet: Y:\MIS_DATABASE\DATASHEETS\DISCRETES\INDUCTORS\74439346068.PDF
R343 = RESISTOR: RES 158K 1/16W 1% 0402; Chkd/date: MANIRAJA/031017; Crtd /date: MANIRAJA/031017; Custom_Duty: 15%; Customs_HS_Code: 85332119; Distributor_name: DIGIKEY; Distributor_part_number: YAG2990CT-ND; Height: 0.40MM; Mfr_name: YAGEO AMERICA; Mfr_part_number: RC0402FR-07158KL; Mistral Part No: 110017100001-R; Package: 0402; Part_type: RESISTORS\FIXED; Project: TI_MAXIE_CPB; RoHS: RoHS; Temperature: -55°C+155°C; Tolerance: 1%; Voltage: NA; Wattage: 1/16W; Weight: 0.65mg; Datasheet: Y:\MIS_DATABASE\DATASHEETS\RESISTORS\YAGEO-RC0402.PDF
R345 = RESISTOR: RES 499K 1/16W 1% 0402; Chkd/date: SUHAS/290910; Crtd /date: MAZHAR/240909; Custom_Duty: 15%; Customs_HS_Code: 85332119; Distributor_name: DIGIKEY; Distributor_part_number: 311-499KLRCT-ND; Height: 0.40MM; Mfr_name: YAGEO AMERICA; Mfr_part_number: RC0402FR-07499KL; Mistral Part No: 110009090015-P; Package: 0402; Part_type: RESISTORS\FIXED; Project: GOLDEN-I; RoHS: Pb-Free; Temperature: -55°C+155°C; Tolerance: 1%; Voltage: 50V; Wattage: 1/16W; Weight: 0.8g/1000pcs; Datasheet: Y:\MIS_DATABASE\DATASHEETS\RESISTORS\YAGEO-RC0402.PDF
R414 = RESISTOR: RES 2.05K 1/10W 1% 0402; Chkd/date: NAVEED/261214; Crtd /date: JEBRAN/271114; Custom_Duty: 15%; Customs_HS_Code: 85332119; Distributor_name: DIGIKEY; Distributor_part_number: P2.05KLCT-ND; Height: 0.40MM; Mfr_name: PANASONIC; Mfr_part_number: ERJ-2RKF2051X; Mistral Part No: 110014110019-R; Package: 0402; Part_type: RESISTORS\FIXED; Project: ZK BIOMETRIC; RoHS: RoHS; Temperature: -55°C+125°C; Tolerance: 1%; Voltage: NA; Wattage: 1/10W; Weight: NA; Datasheet: Y:\MIS_DATABASE\DATASHEETS\RESISTORS\ERJ-2R.PDF
R418 = RESISTOR: RES 10K 1/16W 1% 0402; Chkd/date: VASANTHA/201216; Crtd /date: GEETHA/290506; Custom_Duty: 15%; Customs_HS_Code: 85332119; Distributor_name: DIGIKEY; Distributor_part_number: 311-10.0KLRTR-ND; Footprint Path: Y:\MIS_DATABASE\Library\ALTIUM_TOOL\PCB_FOOTPRINTS\Altium_Footprint_Lib.PcbLib; Height: 0.40MM; Library Path: Y:\MIS_DATABASE\Library\ALTIUM_TOOL\SCHEMATICS_PARTS\MS_DISCRETE_Library.schlib; Mfr_name: YAGEO AMERICA; Mfr_part_number: RC0402FR-0710KL; Mistral Part No: 110009030220-P; Package: 0402; Part_type: RESISTORS\FIXED; Project: VOCERA; RoHS: Pb-Free; Temperature: -55°C+155°C; Tolerance: 1%; Voltage: NA; Wattage: 1/16W; Weight: 0.65mg; Datasheet: Y:\MIS_DATABASE\DATASHEETS\RESISTORS\YAGEO-RC0402.PDF
R419 = RESISTOR: RES 51.1E 1/16W 1% 0402; Chkd/date: MANIRAJA/280617; Crtd /date: MANIRAJA/280617; Custom_Duty: 15%; Customs_HS_Code: 85332119; Distributor_name: DIGIKEY; Distributor_part_number: 311-51.1LRCT-ND; Height: 0.40MM; Mfr_name: YAGEO AMERICA; Mfr_part_number: RC0402FR-0751R1L; Mistral Part No: 110017060001-R; Package: 0402; Part_type: RESISTORS\FIXED; Project: TI_SVB_CONTROLLER CARD; RoHS: RoHS; Temperature: -55°C+155°C; Tolerance: 1%; Voltage: NA; Wattage: 1/16W; Weight: 0.65mg; Datasheet: Y:\MIS_DATABASE\DATASHEETS\RESISTORS\YAGEO-RC0402.PDF
R425 = RESISTOR: RES 31.6K 1/10W 1% 0402; Chkd/date: SHREESHAIL/070606; Crtd /date: SHREESHAIL/070606; Custom_Duty: 15%; Customs_HS_Code: 85332119; Distributor_name: DIGIKEY; Distributor_part_number: P31.6KLCT-ND; Footprint Path: Y:\MIS_DATABASE\Library\ALTIUM_TOOL\PCB_FOOTPRINTS\Altium_Footprint_Lib.PcbLib; Height: 0.40MM; Library Path: Y:\MIS_DATABASE\Library\ALTIUM_TOOL\SCHEMATICS_PARTS\MS_DISCRETE_Library.schlib; Mfr_name: PANASONIC-ECG; Mfr_part_number: ERJ-2RKF3162X; Mistral Part No: 110009030679-R; Package: 0402; Part_type: RESISTORS\FIXED; Project: VOCERA; RoHS: RoHS; Tolerance: 1%; Wattage: 1/10W; Datasheet: Y:\MIS_DATABASE\DATASHEETS\RESISTORS\PAN_ERJ.PDF
R566 = RESISTOR: RES 18.7E 1/16W 1% 0402; Chkd/date: SUHAS/230910; Crtd /date: MUDDU/080910; Custom_Duty: 15%; Customs_HS_Code: 85332119; Distributor_name: DIGIKEY; Distributor_part_number: 541-18.7LCT-ND; Height: 0.40MM; Mfr_name: VISHAY; Mfr_part_number: CRCW040218R7FKED; Mistral Part No: 110010090023-P; Package: 0402; Part_type: RESISTORS\FIXED; Project: ITS; RoHS: Pb-Free; Temperature: -55°C+125°C; Tolerance: 1%; Voltage: 50V; Wattage: 1/16W; Weight: 0.65g/1000pcs; Datasheet: Y:\MIS_DATABASE\DATASHEETS\RESISTORS\CRCW0603.PDF
R567 = RESISTOR: RES 8.87E 1/16W 1% 0402; Chkd/date: USMAN/100114; Crtd /date: JAGADISH/090114; Custom_Duty: 15%; Customs_HS_Code: 85332119; Distributor_name: DIGIKEY; Distributor_part_number: 541-8.87LLCT-ND; Height: 0.40MM; Mfr_name: VISHAY; Mfr_part_number: CRCW04028R87FKED; Mistral Part No: 110014010002-R; Package: 0402; Part_type: RESISTORS\FIXED; Project: ITS2_CC; RoHS: RoHS; Temperature: -55°C+155°C; Tolerance: 1%; Voltage: NA; Wattage: 1/16W; Weight: 0.65mg; Datasheet: Y:\MIS_DATABASE\DATASHEETS\RESISTORS\CRCW0603.PDF
U5 = TPS73501DRVR_SON6: IC 500mA LOW DROPOUT HIGH PSRR LINEAR REGULATOR SON6; Chkd/date: MANIRAJA/161117; Crtd /date: MANIRAJA/161117; Custom_Duty: 15%; Customs_HS_Code: 85423100; Distributor_name: DIGIKEY; Distributor_part_number: 296-27480-1-ND; Height: 0.80MM; Mfr_name: TEXAS INSTRUMENTS; Mistral Part No: 142017110007-R; Package: SON6; Part_type: ICS\POWER\VOLTAGE REGULATOR; Project: TI_MAXIE_CPB; RoHS: RoHS; Temperature: -40°C+125°C; Tolerance: NA; Voltage: NA; Wattage: NA; Weight: 9.7mg; Datasheet: Y:\MIS_DATABASE\DATASHEETS\ICS\POWER\TPS735.PDF
U10 = TPS51206DSQR_WSON10: IC SINK/SOURCE DDR TERMINATION REGULATOR WSON10; Chkd/date: MANIRAJA/220917; Crtd /date: MANIRAJA/220917; Custom_Duty: 15%; Customs_HS_Code: 85423100; Distributor_name: DIGIKEY; Distributor_part_number: 296-28767-1-ND; Height: 0.80MM; Mfr_name: TEXAS INSTRUMENTS; Mistral Part No: 142017090016-R; Package: WSON10; Part_type: ICS\POWER\VOLTAGE REGULATOR; Project: TI_MAXIE_CPB; RoHS: RoHS; Temperature: -40°C+85°C; Tolerance: NA; Voltage: NA; Wattage: NA; Weight: NA; Datasheet: Y:\MIS_DATABASE\DATASHEETS\ICS\POWER\TPS51206.PDF
U64 = TPS62095RGTR_VQFN16: IC 4A STEP DOWN CONVERTER WITH DCS CONTROL VQFN16; Chkd/date: MANIRAJA/031017; Crtd /date: MANIRAJA/031017; Custom_Duty: 15%; Customs_HS_Code: 85423100; Distributor_name: DIGIKEY; Distributor_part_number: 296-40833-1-ND; Height: 1.00MM; Mfr_name: TEXAS INSTRUMENTS; Mistral Part No: 142017100001-R; Package: VQFN16; Part_type: ICS\POWER\CONVERTER; Project: TI_MAXIE_CPB; RoHS: RoHS; Temperature: -40°C+85°C; Tolerance: NA; Voltage: NA; Wattage: NA; Weight: NA; Datasheet: Y:\MIS_DATABASE\DATASHEETS\ICS\POWER\TPS62095.PDF
U80 = TPS54334DRCT_VSON10: IC 3A O/P CURRENT SYNCHRONOUS STEP DOWN VOLTAGE CONVERTER VSON10; Chkd/date: MANIRAJA/270917; Crtd /date: MANIRAJA/270917; Custom_Duty: 15%; Customs_HS_Code: 85423100; Distributor_name: DIGIKEY; Distributor_part_number: 296-42172-2-ND; Height: 1.00MM; Mfr_name: TEXAS INSTRUMENTS; Mistral Part No: 142017090024-R; Package: VSON10; Part_type: ICS\POWER\CONVERTER; Project: TI_MAXIE_CPB; RoHS: RoHS; Temperature: -40°C+85°C; Tolerance: NA; Voltage: NA; Wattage: NA; Weight: 30mg; Datasheet: Y:\MIS_DATABASE\DATASHEETS\ICS\POWER\TPS54334.PDF

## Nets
DGND: C1.2 C2.2 C3.2 C5.2 C14.2 C15.2 C17.2 C22.2 C23.2 C25.2 C37.2 C38.1 C211.2 C212.2 C252.2 C253.2 C255.2 C256.2 C257.2 C258.2 C259.2 C260.2 C261.2 C262.2 C264.2 C265.2 C266.2 C267.2 C268.2 C270.2 C271.2 C272.2 C274.2 C275.2 C323.2 C341.2 C353.2 C357.2 C359.1 C363.2 C366.2 C601.2 C605.2 C606.2 C682.2 C712.2 C713.2 C714.2 C727.2 C728.2 R6.1 R10.2 R11.2 R15.2 R41.2 R340.2 R343.2 R418.2 R567.2 R763.2 R764.2 R789.1 R790.1 U1.2(GND) U1.5(EP) U5.3(GND) U5.7(EP) U10.4(PGND) U10.8(GND) U10.11(EP) U40.1(PGND) U40.11(AGND) U59.A2(AGND) U59.C1(SENSE-) U59.C3(PGND1) U59.C4(PGND2) U59.D4(PGND3) U60.3(GND) U60.7(EP) U61.A1(AGND) U61.B1(PGND) U61.B2(PGND) U61.B3(PGND) U63.1(PGND) U63.11(AGND) U64.6(AGND) U64.14(PGND) U64.15(PGND) U64.17(EP) U80.3(GND) U80.4(GND) U80.5(GND) U80.11(EP) U94.5(GND) U128.3(GND) U130.1(PGND1) U130.11(PGND2) U130.13(AGND) ; also on sheet 11 12 13 14 15 16 17 18 19 20 21 22 23 24 25 26 27 28 29 30 31 32 33 34 35 36 37 38 39 40 43 44
VCC1V0: C4.1 C268.1 C270.1 C274.1 C275.1 C713.1 C714.1 L4.2 L5.2 L13.2 R792.1 TP93.1(TP) ; also on sheet 26
VCC1V2_DDR: C267.1 L6.2 R16.1 TP26.1(TP) U63.3(VOS) ; also on sheet 26
VCC1V2_PG: R12.1 U63.5(PG)
VCC1V8: C605.1 L11.2 TP19.1(TP) U94.3(FB) U94.4(VOS) ; also on sheet 11 18 19 20 21 22 23 26 29 31 33 35 36 37 38 44
VCC2V5_PG: R549.1 U40.5(PG)
VCC3V3_IO: C363.1 C366.1 L9.2 R336.2 R401.1 R419.1 TP20.1(TP) ; also on sheet 11 18 19 20 21 22 23 24 25 26 28 29 30 31 33 34 35 36 37 38 39 43 44
VCC3V3_PREREG: C1.1 C15.1 C23.1 C25.1 C211.1 C252.1 C253.1 C255.1 C256.1 C257.1 C260.1 C262.1 C606.1 C712.1 C727.1 C728.1 R4.2 R7.1 R8.1 R12.2 R345.1 R549.2 U1.4(IN) U5.6(IN) U10.2(VLDOIN) U10.10(VDD) U40.7(PVIN) U40.8(AVIN) U59.A1(AVIN) U59.A4(VIN) U60.6(IN) U61.D1(VIN1) U61.D2(VIN2) U61.D3(VIN3) U63.7(PVIN) U63.8(AVIN) U64.3(DEF) U64.10(AVIN) U64.11(PVIN) U64.12(PVIN) U94.7(VIN) U128.5(VCC) U130.3(VIN1) U130.9(VIN2) ; also on sheet 13 39 40
VCC3V3_PREREG_PG: TP83.1(TP) U5.4(EN) U40.6(EN) U80.8(EN) ; also on sheet 40
VCC_2V5: C17.1 TP82.1(TP) U5.1(OUT) ; also on sheet 17 35
VDD1V8_PG: C258.1 R336.1 R781.2 R787.2 R788.2 R794.2 TP81.1(TP) U60.5(PG) U94.2(PG)
VDD1V8_PG_CORE1: R788.1 R790.2 U130.4(EN)
VDD1V8_PG_CORE2: R787.1 R789.2 U61.E1(EN)
VDD_1V0: C271.1 C272.1 L7.2 R344.1 TP27.1(TP) U64.16(VOS) ; also on sheet 13 21 22 23 33 35
VDD_1V0_PG: R345.2 U64.4(PG)
VDD_2V5: C212.1 L2.2 R566.1 TP64.1(TP) U40.3(VOS) ; also on sheet 21 22 23 33
VDD_CORE: R339.1 R791.1 ; also on sheet 12 13 26 39
VDD_CORE_PG_INV: R763.1 TP91.1(TP) U61.A2(VSET/~{PG}) U128.2(A)
VDD_DDR4: C22.1 U10.1(VDDQSNS) ; also on sheet 16 17 26
VDD_MPU: U59.B1(SENSE+) ; also on sheet 12 26 39
VDD_MPU_EN: R781.1 R793.2 TP79.1(TP) U59.A3(VSEL1) U59.B2(EN) U59.C2(VSEL0) U128.4(Y)
VDDA1V8: C259.1 R762.1 TP22.1(TP) U60.1(OUT) ; also on sheet 26
VDDR_VTT: C38.2 TP5.1(TP) U10.3(VTT) U10.5(VTTSNS) ; also on sheet 17
VIN_MON_PORz_3V3_PG: C353.1 R401.2 TP76.1(TP) U60.4(EN) U63.6(EN) U80.10(PGOOD) U94.1(EN) ; also on sheet 39
DDR_VREFCA: C37.1 U10.6(VTTREF) ; also on sheet 16 17
DDR_VTT_EN_3V3: R41.1 TP84.1(TP) U10.7(S3) U10.9(S5) ; also on sheet 37
RESET_SoC_MPU: C682.1 U59.D1(VDD) ; also on sheet 37
SoC_MPU: C261.1 C266.1 L3.2 TP24.1(TP) ; also on sheet 26
SOC_WKUP_SCL: U59.D3(SCL) U61.E3(SCL) ; also on sheet 20 33 34 35 44
SOC_WKUP_SDA: U59.D2(SDA) U61.E2(SDA) ; also on sheet 20 33 34 35 44
TG: R4.1 TP3.1(TP) U130.7(TG)
VMAIN: C323.1 C341.1 U80.1(VIN) ; also on sheet 39 40 43
VPP_1V8: C5.1 TP23.1(TP) U1.1(OUT) ; also on sheet 13
VPP_LDO_EN: R6.2 TP80.1(TP) U1.3(EN) ; also on sheet 19
VSENSE: C361.2 R418.1 R425.2 U80.6(VSENSE)
N17781485: L11.1 U94.6(SW)
N17781689: L6.1 U63.2(SW)
N17781701: R15.1 R16.2 U63.4(FB)
N17781734: L3.1 U59.B3(SW1) U59.B4(SW2)
N17785459: C357.1 R414.1 U80.7(COMP)
N17785463: C359.2 R414.2
N17785477: C356.2 L9.1 U80.2(SW)
N17785481: C356.1 U80.9(BOOT)
N17785497: C361.1 R419.2 R425.1
N17785579: L7.1 U64.1(SW1) U64.2(SW2)
N17785692: C269.2 U64.7(CP)
N17785694: C269.1 U64.8(CN)
N17785722: R343.1 R344.2 U64.5(FB)
N17786037: L2.1 U40.2(SW)
N17786049: R566.2 R567.1 U40.4(FB)
N18550089: C3.1 U63.9(SS/TR)
N19031494: C601.1 U40.9(SS/TR)
N19031660: C264.1 U64.9(SS)
N20142928: C14.1 U5.2(NR/FB)
N23079966: R762.2 R764.1 U60.2(FB)
N23093100: L4.1 U61.C1(SW1) U61.C2(SW2) U61.C3(SW3)
N23956430: C265.1 U130.12(SS/TR)
N23956432: C4.2 R339.2 R340.1 R341.2 U130.14(FB)
N23956434: R10.1 U130.6(VSEL)
N23956518: C2.1 R8.2 R793.1 U130.5(PG)
N23956734: R7.2 R11.1 U130.8(MODE)
N23956742: L5.1 U130.2(SW1)
N23956744: L13.1 U130.10(SW2)
N23956762: R792.2 U130.16(VO)
N23956795: R341.1 U130.15(RS)
N24018720: R791.2 U61.A3(VOS)
N24136473: R794.1 U64.13(EN)

Not connected (* = marked no-connect by the designer): U5 5(NC)*; U40 10(MODE)*; U63 10(MODE)*; U128 1(NC)*

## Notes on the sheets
sheet 41
- SoC POWER SUPPLY
- 0.9-1.35V, 3.0AMPS SUPPLY
- 1.8V IO, 3.0AMPS SUPPLY
- Default Output voltage is set to 1V
- 1.2V, 2.0AMPS SUPPLY
- VDD_CORE 1.0V, 6.0AMPS SUPPLY (Optional)
- I2C address is 0x43
- 1.8V VPP, 0.15AMPS SUPPLY
- VDD_CORE 1.0V, 6.0AMPS SUPPLY
- 1.8V Analog , 1AMPS SUPPLY
sheet 42
- PERIPHERAL POWER SUPPLY
- 3.3V, 3.0AMPS SUPPLY
- VTT SUPPLY FOR DDR4
- 2.5V, 2.0AMPS SUPPLY
- 1.0V ETHERNET PHY POWER SUPPLY
- 2.5V, .5 AMPS SUPPLY
